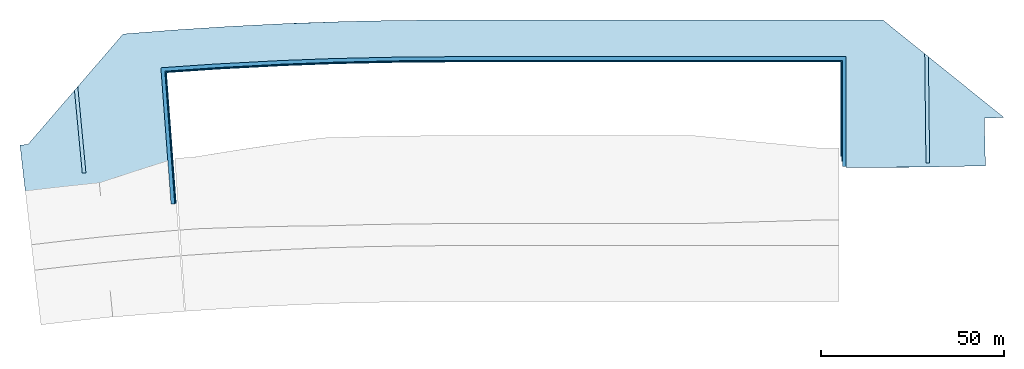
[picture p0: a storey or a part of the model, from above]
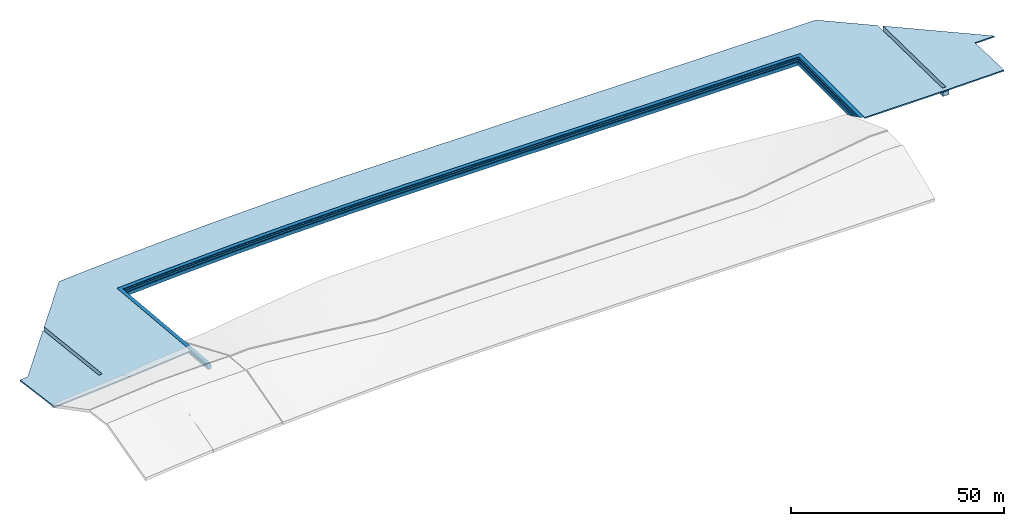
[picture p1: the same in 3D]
Properties of the parts of a building model (IFC2X3)

# File
Description: ViewDefinition [CoordinationView_V2.0]
Time: 2021-10-13T23:41:44
Written by: The EXPRESS Data Manager Version 5.02.0100.07 : 28 Aug 2013
Made in: 22.0.2.392 - Exporter 22.0.2.392 - 代替 UI 22.0.2.392
Comment: STEP Physical File produced by: The EXPRESS Data Manager Version 5.02.0100.07 : 28 Aug 2013 * Module: EDMstepFileFactory/EDMstandAlone * Creation date: Wed Oct 13 23:41:44 2021 * Host: a7687-tada2 * Database: C:\Users\a7687\AppData\Local\Temp\b5ad18af-0434-48c8-a3b0-0a2e87d25636\f20f8c54-2590-4b4c-a1ad-ce8472db91cb\ifc * Database version: 5507 * Database creation date: Wed Oct 13 23:41:34 2021 * Schema: IFC2X3 * Model: DataRepository.ifc * Model creation date: Wed Oct 13 23:41:34 2021 * Header model: DataRepository.ifc_HeaderModel * Header model creation date: Wed Oct 13 23:41:34 2021 * EDMuser: sdai-user * EDMgroup: sdai-group * License ID and type: 5605 : Permanent license. Expiry date: * EDMstepFileFactory options: 020000

# IfcSite, Default
RefLatitude: 35, 53, 9, 550781; RefLongitude: 140, 22, 58, 619384; RefElevation: 0 mm

# IfcSite: アスファルト:アスファルト, アスファルト:アスファルト:829654
Material: <Unnamed>

# IfcSite: アスファルトコンクリート3:アスファルトコンクリート, アスファルトコンクリート3:アスファルトコンクリート:771863
Material: <Unnamed>
Pset_DrainageReserve - Width: 750 mm

# IfcBuilding
Pset_BuildingCommon - NumberOfStoreys: 6

# IfcBuildingStorey: レベル:レベル 上表示 (6)
Name | LongName | Elevation (mm)
DL | DL | 0
AP+9.500 | AP+9.500 | 9500
AP+10.600 | AP+10.600 | 10600
AP+11.000 | AP+11.000 | 11000
AP+12.500 | AP+12.500 | 12500
AP+16813 | AP+16813 | 16813

# IfcBuildingElementProxy: アスファルトコンクリート:アスファルトコンクリート, アスファルトコンクリート:アスファルトコンクリート:789929
In: AP+11.000
Type - Material: <Unnamed>
Pset_BuildingElementProxyCommon - Reference: アスファルトコンクリート; sets with these values: 2

# IfcBuildingElementProxy: 鋼矢板10H型:鋼矢板10H型 (546)
Type - Material: <Unnamed>
Pset_BuildingElementProxyCommon - Reference: 鋼矢板10H型; sets with these values: 2
Name (鋼矢板10H型:鋼矢板10H型:...) | In | Width (mm) = Depth (mm)
775486 | AP+9.500 | 3000
775677 | AP+9.500 | 3000
775771 | AP+9.500 | 3000
775784 | AP+9.500 | 3000
775787 | AP+9.500 | 3000
775790 | AP+9.500 | 3000
775793 | AP+9.500 | 3000
775796 | AP+9.500 | 3000
775799 | AP+9.500 | 3000
775802 | AP+9.500 | 3000
775805 | AP+9.500 | 3000
775808 | AP+9.500 | 3000
775811 | AP+9.500 | 3000
775814 | AP+9.500 | 3000
775817 | AP+9.500 | 3000
775820 | AP+9.500 | 3000
775823 | AP+9.500 | 3000
775826 | AP+9.500 | 3000
775829 | AP+9.500 | 3000
775832 | AP+9.500 | 3000
775835 | AP+9.500 | 3000
775838 | AP+9.500 | 3000
775841 | AP+9.500 | 3000
775844 | AP+9.500 | 3000
775847 | AP+9.500 | 3000
775850 | AP+9.500 | 3000
775853 | AP+9.500 | 3000
775856 | AP+9.500 | 3000
775859 | AP+9.500 | 3000
775862 | AP+9.500 | 3000
775865 | AP+9.500 | 3000
775868 | AP+9.500 | 3000
775871 | AP+9.500 | 3000
775874 | AP+9.500 | 3000
775877 | AP+9.500 | 3000
775880 | AP+9.500 | 3000
775883 | AP+9.500 | 3000
775886 | AP+9.500 | 3000
775889 | AP+9.500 | 3000
775892 | AP+9.500 | 3000
775895 | AP+9.500 | 3000
775898 | AP+9.500 | 3000
775901 | AP+9.500 | 3000
775904 | AP+9.500 | 3000
775907 | AP+9.500 | 3000
775910 | AP+9.500 | 3000
775913 | AP+9.500 | 3000
775916 | AP+9.500 | 3000
775919 | AP+9.500 | 3000
775922 | AP+9.500 | 3000
775925 | AP+9.500 | 3000
775928 | AP+9.500 | 3000
775931 | AP+9.500 | 3000
775934 | AP+9.500 | 3000
775937 | AP+9.500 | 3000
775940 | AP+9.500 | 3000
775943 | AP+9.500 | 3000
775946 | AP+9.500 | 3000
775949 | AP+9.500 | 3000
775952 | AP+9.500 | 3000
775955 | AP+9.500 | 3000
775958 | AP+9.500 | 3000
775961 | AP+9.500 | 3000
775964 | AP+9.500 | 3000
775967 | AP+9.500 | 3000
775970 | AP+9.500 | 3000
775973 | AP+9.500 | 3000
775976 | AP+9.500 | 3000
775979 | AP+9.500 | 3000
775982 | AP+9.500 | 3000
775985 | AP+9.500 | 3000
775988 | AP+9.500 | 3000
775991 | AP+9.500 | 3000
775994 | AP+9.500 | 3000
775997 | AP+9.500 | 3000
776000 | AP+9.500 | 3000
776003 | AP+9.500 | 3000
776006 | AP+9.500 | 3000
776009 | AP+9.500 | 3000
776012 | AP+9.500 | 3000
776015 | AP+9.500 | 3000
776018 | AP+9.500 | 3000
776021 | AP+9.500 | 3000
776024 | AP+9.500 | 3000
776027 | AP+9.500 | 3000
776030 | AP+9.500 | 3000
776033 | AP+9.500 | 3000
776036 | AP+9.500 | 3000
776039 | AP+9.500 | 3000
776042 | AP+9.500 | 3000
776045 | AP+9.500 | 3000
776048 | AP+9.500 | 3000
776051 | AP+9.500 | 3000
776054 | AP+9.500 | 3000
776057 | AP+9.500 | 3000
776060 | AP+9.500 | 3000
776063 | AP+9.500 | 3000
776066 | AP+9.500 | 3000
776069 | AP+9.500 | 3000
776072 | AP+9.500 | 3000
776075 | AP+9.500 | 3000
776078 | AP+9.500 | 3000
776081 | AP+9.500 | 3000
776084 | AP+9.500 | 3000
776087 | AP+9.500 | 3000
776090 | AP+9.500 | 3000
776093 | AP+9.500 | 3000
776096 | AP+9.500 | 3000
776099 | AP+9.500 | 3000
776102 | AP+9.500 | 3000
776105 | AP+9.500 | 3000
776108 | AP+9.500 | 3000
776111 | AP+9.500 | 3000
776114 | AP+9.500 | 3000
776117 | AP+9.500 | 3000
776120 | AP+9.500 | 3000
776123 | AP+9.500 | 3000
776126 | AP+9.500 | 3000
777359 | AP+9.500 | 3000
777398 | AP+9.500 | 3000
777410 | AP+9.500 | 3000
777422 | AP+9.500 | 3000
777432 | AP+9.500 | 3000
777440 | AP+9.500 | 3000
777462 | AP+9.500 | 3000
777472 | AP+9.500 | 3000
777490 | AP+9.500 | 3000
777498 | AP+9.500 | 3000
777510 | AP+9.500 | 3000
777518 | AP+9.500 | 3000
777528 | AP+9.500 | 3000
777540 | AP+9.500 | 3000
777550 | AP+9.500 | 3000
777558 | AP+9.500 | 3000
777566 | AP+9.500 | 3000
777578 | AP+9.500 | 3000
777586 | AP+9.500 | 3000
777598 | AP+9.500 | 3000
777608 | AP+9.500 | 3000
777616 | AP+9.500 | 3000
777626 | AP+9.500 | 3000
777636 | AP+9.500 | 3000
777648 | AP+9.500 | 3000
777656 | AP+9.500 | 3000
777666 | AP+9.500 | 3000
777674 | AP+9.500 | 3000
777684 | AP+9.500 | 3000
777694 | AP+9.500 | 3000
777702 | AP+9.500 | 3000
777710 | AP+9.500 | 3000
777720 | AP+9.500 | 3000
777732 | AP+9.500 | 3000
777740 | AP+9.500 | 3000
777748 | AP+9.500 | 3000
777758 | AP+9.500 | 3000
777768 | AP+9.500 | 3000
777780 | AP+9.500 | 3000
777806 | AP+9.500 | 3000
777816 | AP+9.500 | 3000
777826 | AP+9.500 | 3000
777836 | AP+9.500 | 3000
777844 | AP+9.500 | 3000
777854 | AP+9.500 | 3000
777864 | AP+9.500 | 3000
777874 | AP+9.500 | 3000
777882 | AP+9.500 | 3000
777890 | AP+9.500 | 3000
777898 | AP+9.500 | 3000
777908 | AP+9.500 | 3000
777918 | AP+9.500 | 3000
777928 | AP+9.500 | 3000
777936 | AP+9.500 | 3000
777948 | AP+9.500 | 3000
777962 | AP+9.500 | 3000
777972 | AP+9.500 | 3000
777984 | AP+9.500 | 3000
777994 | AP+9.500 | 3000
778004 | AP+9.500 | 3000
778014 | AP+9.500 | 3000
778024 | AP+9.500 | 3000
778034 | AP+9.500 | 3000
778042 | AP+9.500 | 3000
778050 | AP+9.500 | 3000
778058 | AP+9.500 | 3000
778068 | AP+9.500 | 3000
778078 | AP+9.500 | 3000
778088 | AP+9.500 | 3000
778098 | AP+9.500 | 3000
778108 | AP+9.500 | 3000
778116 | AP+9.500 | 3000
778124 | AP+9.500 | 3000
778132 | AP+9.500 | 3000
778142 | AP+9.500 | 3000
778152 | AP+9.500 | 3000
778160 | AP+9.500 | 3000
778168 | AP+9.500 | 3000
778176 | AP+9.500 | 3000
778186 | AP+9.500 | 3000
778196 | AP+9.500 | 3000
778204 | AP+9.500 | 3000
778212 | AP+9.500 | 3000
778222 | AP+9.500 | 3000
778234 | AP+9.500 | 3000
778242 | AP+9.500 | 3000
778252 | AP+9.500 | 3000
778428 | AP+9.500 | 3000
778441 | AP+9.500 | 3000
778444 | AP+9.500 | 3000
778447 | AP+9.500 | 3000
778450 | AP+9.500 | 3000
778453 | AP+9.500 | 3000
778456 | AP+9.500 | 3000
778459 | AP+9.500 | 3000
778462 | AP+9.500 | 3000
778465 | AP+9.500 | 3000
778468 | AP+9.500 | 3000
778471 | AP+9.500 | 3000
778474 | AP+9.500 | 3000
778477 | AP+9.500 | 3000
778480 | AP+9.500 | 3000
778483 | AP+9.500 | 3000
778486 | AP+9.500 | 3000
778489 | AP+9.500 | 3000
778492 | AP+9.500 | 3000
778495 | AP+9.500 | 3000
778498 | AP+9.500 | 3000
778501 | AP+9.500 | 3000
778504 | AP+9.500 | 3000
778507 | AP+9.500 | 3000
778510 | AP+9.500 | 3500
778513 | AP+9.500 | 3500
778516 | AP+9.500 | 4000
778519 | AP+9.500 | 4500
778522 | AP+9.500 | 4500
778525 | AP+9.500 | 5000
778528 | AP+9.500 | 5500
778531 | AP+9.500 | 5500
778534 | AP+9.500 | 6000
778537 | AP+9.500 | 6500
778540 | AP+9.500 | 6500
778543 | AP+9.500 | 7000
778546 | AP+9.500 | 7500
778549 | AP+9.500 | 7500
778552 | AP+9.500 | 8000
778555 | AP+9.500 | 8500
778558 | AP+9.500 | 8500
778561 | AP+9.500 | 9000
778564 | AP+9.500 | 9500
778567 | AP+9.500 | 10000
778570 | AP+9.500 | 10000
778573 | AP+9.500 | 10500
778576 | AP+9.500 | 10500
778579 | AP+9.500 | 10500
778582 | AP+9.500 | 10500
778585 | AP+9.500 | 10500
778588 | AP+9.500 | 10500
778591 | AP+9.500 | 10500
778594 | AP+9.500 | 10500
778597 | AP+9.500 | 10500
778600 | AP+10.600 | 10500
778603 | AP+10.600 | 10000
778606 | AP+10.600 | 10000
778609 | AP+10.600 | 9500
778612 | AP+10.600 | 9000
778615 | AP+10.600 | 8500
778618 | AP+10.600 | 8500
778621 | AP+10.600 | 8000
778624 | AP+10.600 | 7500
778627 | AP+10.600 | 7000
778630 | AP+10.600 | 7000
778633 | AP+10.600 | 6500
778636 | AP+10.600 | 6000
778639 | AP+10.600 | 6000
778642 | AP+10.600 | 5500
778645 | AP+10.600 | 5000
778648 | AP+10.600 | 4500
778685 | AP+10.600 | 3000
778686 | AP+10.600 | 3000
778687 | AP+10.600 | 3000
778688 | AP+10.600 | 3000
778689 | AP+10.600 | 3000
778690 | AP+10.600 | 3000
778691 | AP+10.600 | 3000
778692 | AP+10.600 | 3000
778693 | AP+10.600 | 3000
778694 | AP+10.600 | 3000
778695 | AP+10.600 | 3000
778696 | AP+10.600 | 3000
778697 | AP+10.600 | 3000
778698 | AP+10.600 | 3000
778699 | AP+10.600 | 3000
778700 | AP+10.600 | 3000
778701 | AP+10.600 | 3000
778702 | AP+10.600 | 3000
778703 | AP+10.600 | 3000
778704 | AP+10.600 | 3000
778705 | AP+10.600 | 3000
778706 | AP+10.600 | 3000
778707 | AP+10.600 | 3000
778708 | AP+10.600 | 3000
778709 | AP+10.600 | 3000
778710 | AP+10.600 | 3000
778711 | AP+10.600 | 3000
778712 | AP+10.600 | 3000
778713 | AP+10.600 | 3000
778714 | AP+10.600 | 3000
778715 | AP+10.600 | 3000
778716 | AP+10.600 | 3000
778717 | AP+10.600 | 3000
778718 | AP+10.600 | 3000
778719 | AP+10.600 | 3000
778720 | AP+10.600 | 3000
778721 | AP+10.600 | 3000
778722 | AP+10.600 | 3000
778723 | AP+10.600 | 3000
778724 | AP+10.600 | 3000
778725 | AP+10.600 | 3000
778726 | AP+10.600 | 3000
778727 | AP+10.600 | 3000
778728 | AP+10.600 | 3000
778729 | AP+10.600 | 3000
778730 | AP+10.600 | 3000
778731 | AP+10.600 | 3000
778732 | AP+10.600 | 3000
778733 | AP+10.600 | 3000
778734 | AP+10.600 | 3000
778735 | AP+10.600 | 3000
778736 | AP+10.600 | 3000
778737 | AP+10.600 | 3000
778738 | AP+10.600 | 3000
778739 | AP+10.600 | 3000
778740 | AP+10.600 | 3000
778741 | AP+10.600 | 3000
778742 | AP+10.600 | 3000
778743 | AP+10.600 | 3000
778744 | AP+10.600 | 3000
778745 | AP+10.600 | 3000
778746 | AP+10.600 | 3000
778747 | AP+10.600 | 3000
778748 | AP+10.600 | 3000
778749 | AP+10.600 | 3000
778750 | AP+10.600 | 3000
778751 | AP+10.600 | 3000
778752 | AP+10.600 | 3000
778753 | AP+10.600 | 3000
778754 | AP+10.600 | 3000
778755 | AP+10.600 | 3000
778756 | AP+10.600 | 3000
778757 | AP+10.600 | 3000
778758 | AP+10.600 | 3000
778759 | AP+10.600 | 3000
778760 | AP+10.600 | 3000
778761 | AP+10.600 | 3000
778762 | AP+10.600 | 3000
778763 | AP+10.600 | 3000
778764 | AP+10.600 | 3000
778765 | AP+10.600 | 3000
778766 | AP+10.600 | 3000
778767 | AP+10.600 | 3000
778768 | AP+10.600 | 3000
778769 | AP+10.600 | 3000
778770 | AP+10.600 | 3000
778771 | AP+10.600 | 3000
778772 | AP+10.600 | 3000
778773 | AP+10.600 | 3000
778774 | AP+10.600 | 3000
778775 | AP+10.600 | 3000
778776 | AP+10.600 | 3000
778777 | AP+10.600 | 3000
778778 | AP+10.600 | 3000
778779 | AP+10.600 | 3000
778780 | AP+10.600 | 3000
778781 | AP+10.600 | 3000
778782 | AP+10.600 | 3000
778783 | AP+10.600 | 3000
778784 | AP+10.600 | 3000
778785 | AP+10.600 | 3000
778786 | AP+10.600 | 3000
778787 | AP+10.600 | 3000
778788 | AP+10.600 | 3000
778789 | AP+10.600 | 3000
778790 | AP+10.600 | 3000
778791 | AP+10.600 | 3000
778792 | AP+10.600 | 3000
778793 | AP+10.600 | 3000
778794 | AP+10.600 | 3000
778795 | AP+10.600 | 3000
778796 | AP+10.600 | 3000
778797 | AP+10.600 | 3000
778798 | AP+10.600 | 3000
778799 | AP+10.600 | 3000
778800 | AP+10.600 | 3000
778801 | AP+10.600 | 3000
778845 | AP+10.600 | 3000
778865 | AP+10.600 | 3000
778875 | AP+10.600 | 3000
778883 | AP+10.600 | 3000
778893 | AP+10.600 | 3000
778903 | AP+10.600 | 3000
778913 | AP+10.600 | 3000
778921 | AP+10.600 | 3000
778931 | AP+10.600 | 3000
778941 | AP+10.600 | 3000
778951 | AP+10.600 | 3000
778961 | AP+10.600 | 3000
778969 | AP+10.600 | 3000
778981 | AP+10.600 | 3000
778991 | AP+10.600 | 3000
779001 | AP+10.600 | 3000
779011 | AP+10.600 | 3000
779021 | AP+10.600 | 3000
779031 | AP+10.600 | 3000
779039 | AP+10.600 | 3000
779049 | AP+10.600 | 3000
779059 | AP+10.600 | 3000
779071 | AP+10.600 | 3000
779081 | AP+10.600 | 3000
779091 | AP+10.600 | 3000
779099 | AP+10.600 | 3000
779111 | AP+10.600 | 3000
779123 | AP+10.600 | 3000
779131 | AP+10.600 | 3000
779141 | AP+10.600 | 3000
779149 | AP+10.600 | 3000
779161 | AP+10.600 | 3000
779171 | AP+10.600 | 3000
779181 | AP+10.600 | 3000
779193 | AP+10.600 | 3000
779203 | AP+10.600 | 3000
779215 | AP+10.600 | 3000
779225 | AP+10.600 | 3000
779235 | AP+10.600 | 3000
779245 | AP+10.600 | 3000
779255 | AP+10.600 | 3000
779265 | AP+10.600 | 3000
779275 | AP+10.600 | 3000
779285 | AP+10.600 | 3000
779295 | AP+10.600 | 3000
779307 | AP+10.600 | 3000
779319 | AP+10.600 | 3000
779331 | AP+10.600 | 3000
779343 | AP+10.600 | 3000
779353 | AP+10.600 | 3000
779363 | AP+10.600 | 3000
779375 | AP+10.600 | 3000
779383 | AP+10.600 | 3000
779391 | AP+10.600 | 3000
779403 | AP+10.600 | 3000
779411 | AP+10.600 | 3000
779423 | AP+10.600 | 3000
779433 | AP+10.600 | 3000
779443 | AP+10.600 | 3000
779455 | AP+10.600 | 3000
779465 | AP+10.600 | 3000
779473 | AP+10.600 | 3000
779483 | AP+10.600 | 3000
779491 | AP+10.600 | 3000
779501 | AP+10.600 | 3000
779513 | AP+10.600 | 3000
779523 | AP+10.600 | 3000
779533 | AP+10.600 | 3000
779547 | AP+10.600 | 3000
779557 | AP+10.600 | 3000
779567 | AP+10.600 | 3000
779575 | AP+10.600 | 3000
779585 | AP+10.600 | 3000
779595 | AP+10.600 | 3000
779605 | AP+10.600 | 3000
779615 | AP+10.600 | 3000
779623 | AP+10.600 | 3000
779631 | AP+10.600 | 3000
779641 | AP+10.600 | 3000
779651 | AP+10.600 | 3000
779661 | AP+10.600 | 3000
794716 | AP+9.500 | 3000
794725 | AP+9.500 | 3000
794726 | AP+9.500 | 3000
794727 | AP+9.500 | 3000
794728 | AP+9.500 | 3000
794729 | AP+9.500 | 3000
794730 | AP+9.500 | 3000
794731 | AP+9.500 | 3000
794732 | AP+9.500 | 3000
794733 | AP+9.500 | 3000
794734 | AP+9.500 | 3000
794735 | AP+9.500 | 3000
794736 | AP+9.500 | 3000
794737 | AP+9.500 | 3000
794738 | AP+9.500 | 3000
794739 | AP+9.500 | 3000
794740 | AP+9.500 | 3000
794741 | AP+9.500 | 3000
794742 | AP+9.500 | 3000
794743 | AP+9.500 | 3000
794744 | AP+9.500 | 3000
794745 | AP+9.500 | 3000
794746 | AP+9.500 | 3000
794747 | AP+9.500 | 3000
794748 | AP+9.500 | 3000
794749 | AP+9.500 | 3500
794750 | AP+9.500 | 3500
794751 | AP+9.500 | 4000
794752 | AP+9.500 | 4500
794753 | AP+9.500 | 4500
794754 | AP+9.500 | 5000
794755 | AP+9.500 | 5500
794756 | AP+9.500 | 5500
794757 | AP+9.500 | 6000
794758 | AP+9.500 | 6500
794759 | AP+9.500 | 6500
794760 | AP+9.500 | 7000
794761 | AP+9.500 | 7500
794762 | AP+9.500 | 7500
794763 | AP+9.500 | 8000
794764 | AP+9.500 | 8500
794765 | AP+9.500 | 8500
794766 | AP+9.500 | 9000
794767 | AP+9.500 | 9500
794768 | AP+9.500 | 10000
794769 | AP+9.500 | 10000
794770 | AP+9.500 | 10500
794771 | AP+9.500 | 10500
794772 | AP+9.500 | 10500
794773 | AP+9.500 | 10500
794774 | AP+9.500 | 10500
794775 | AP+9.500 | 10500
794776 | AP+9.500 | 10500
794777 | AP+9.500 | 10500
794778 | AP+9.500 | 10500
794779 | AP+10.600 | 10500
794780 | AP+10.600 | 10000
794781 | AP+10.600 | 10000
794782 | AP+10.600 | 9500
794783 | AP+10.600 | 9000
794784 | AP+10.600 | 8500
794785 | AP+10.600 | 8500
794786 | AP+10.600 | 8000
794787 | AP+10.600 | 7500
794788 | AP+10.600 | 7000
794789 | AP+10.600 | 7000
794790 | AP+10.600 | 6500
794791 | AP+10.600 | 6000
794792 | AP+10.600 | 6000
794793 | AP+10.600 | 5500
794794 | AP+10.600 | 5000
794795 | AP+10.600 | 4500

# IfcSlab: かごマット2:かごマット, かごマット2:かごマット:790178
In: DL
Type - PredefinedType: BASESLAB
Type - Pset_SlabCommon - IsExternal: no
Pset_QuantityTakeOff - Reference: かごマット; sets with these values: 2
Pset_SlabCommon - Reference: かごマット

# IfcSlab: かごマット3:かごマット, かごマット3:かごマット:791961
In: AP+9.500
Type - PredefinedType: BASESLAB
Type - Pset_SlabCommon - IsExternal: no
Pset_QuantityTakeOff - Reference: かごマット; sets with these values: 2
Pset_SlabCommon - Reference: かごマット

# IfcSlab: かごマット段:かごマット, かごマット段:かごマット:775482
In: DL
Type - PredefinedType: BASESLAB
Type - Pset_SlabCommon - IsExternal: no
Pset_QuantityTakeOff - Reference: かごマット; sets with these values: 2
Pset_SlabCommon - Reference: かごマット

# IfcSlab: アスファルトコンクリート2:アスファルトコンクリート, アスファルトコンクリート2:アスファルトコンクリート:789337
In: DL
Type - PredefinedType: BASESLAB
Type - Pset_SlabCommon - IsExternal: no
Pset_QuantityTakeOff - Reference: アスファルトコンクリート; sets with these values: 2
Pset_SlabCommon - Reference: アスファルトコンクリート

# IfcSlab: 大型連節ブロック2:大型連節ブロック, 大型連節ブロック2:大型連節ブロック:834103
In: AP+9.500
Type - PredefinedType: BASESLAB
Type - Pset_SlabCommon - IsExternal: no
Pset_QuantityTakeOff - Reference: 大型連節ブロック; sets with these values: 2
Pset_SlabCommon - Reference: 大型連節ブロック

# IfcSlab: 大型連節ブロック:大型連節ブロック, 大型連節ブロック:大型連節ブロック:790782
In: DL
Type - PredefinedType: BASESLAB
Type - Pset_SlabCommon - IsExternal: no
Pset_QuantityTakeOff - Reference: 大型連節ブロック; sets with these values: 2
Pset_SlabCommon - Reference: 大型連節ブロック

# IfcSlab: 笠コンクリート:笠コンクリート, 笠コンクリート:笠コンクリート:783542
In: AP+9.500
Type - PredefinedType: BASESLAB
Type - Pset_SlabCommon - IsExternal: no
Pset_QuantityTakeOff - Reference: 笠コンクリート; sets with these values: 2
Pset_SlabCommon - Reference: 笠コンクリート
